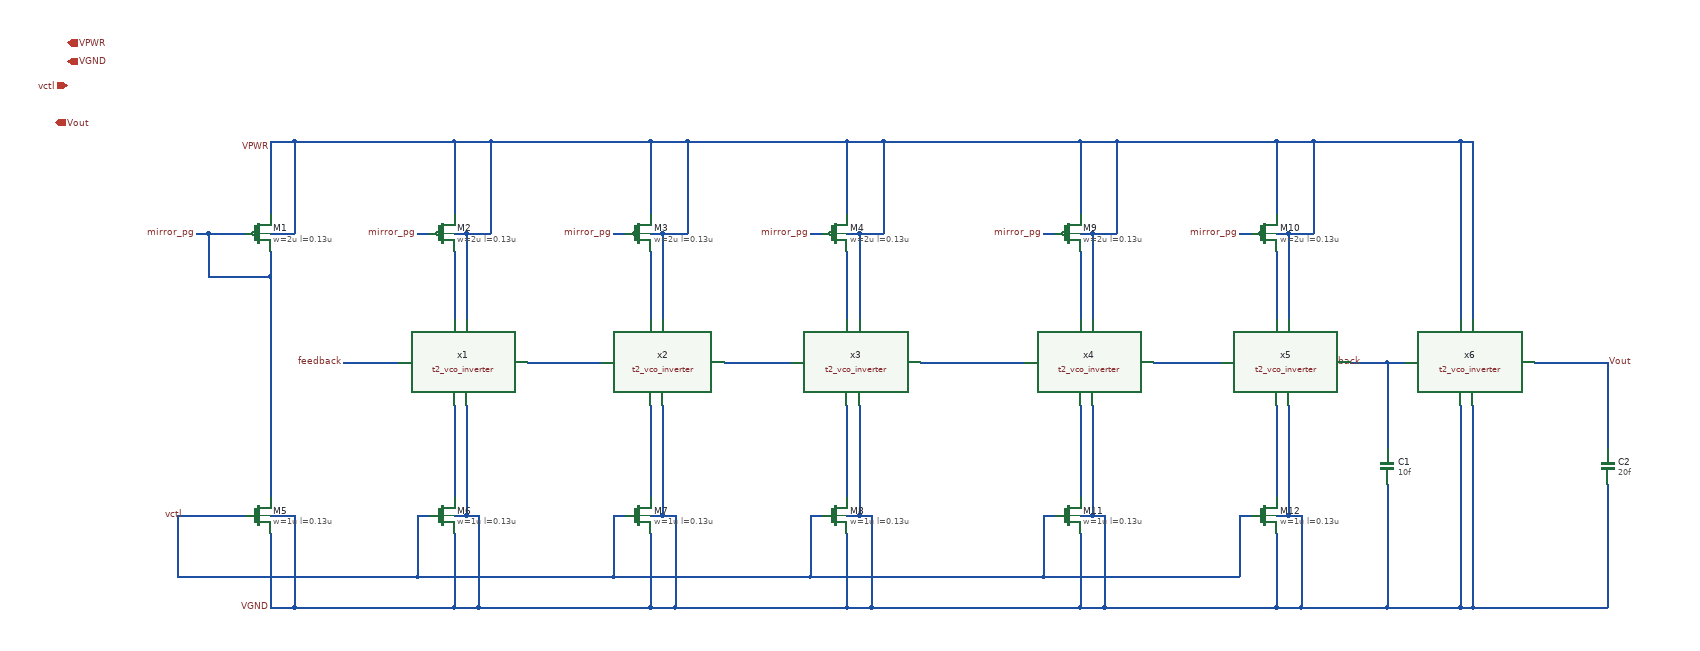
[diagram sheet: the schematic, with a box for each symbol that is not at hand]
v {xschem version=3.4.7 file_version=1.2}
G {}
K {}
V {}
S {}
E {}
N 290 720 550 720 {lab=VGND}
N 100 570 210 570 {lab=vctl}
N 250 570 290 570 {lab=VGND}
N 290 570 290 720 {lab=VGND}
N 250 600 250 720 {lab=VGND}
N 570 570 590 570 {lab=VGND}
N 590 570 590 720 {lab=VGND}
N 550 600 550 720 {lab=VGND}
N 890 570 910 570 {lab=VGND}
N 910 570 910 720 {lab=VGND}
N 870 600 870 720 {lab=VGND}
N 1210 570 1230 570 {lab=VGND}
N 1230 570 1230 720 {lab=VGND}
N 1190 600 1190 720 {lab=VGND}
N 290 -40 550 -40 {lab=VPWR}
N 610 -40 870 -40 {lab=VPWR}
N 930 -40 1190 -40 {lab=VPWR}
N 250 180 250 540 {lab=mirror_pg}
N 150 110 210 110 {lab=mirror_pg}
N 150 110 150 180 {lab=mirror_pg}
N 150 180 250 180 {lab=mirror_pg}
N 250 140 250 180 {lab=mirror_pg}
N 250 110 290 110 {lab=VPWR}
N 250 -40 250 80 {lab=VPWR}
N 570 110 610 110 {lab=VPWR}
N 550 -40 550 80 {lab=VPWR}
N 890 110 930 110 {lab=VPWR}
N 870 -40 870 80 {lab=VPWR}
N 1210 110 1250 110 {lab=VPWR}
N 1190 -40 1190 80 {lab=VPWR}
N 590 720 870 720 {lab=VGND}
N 910 720 1190 720 {lab=VGND}
N 1950 -40 2190 -40 {lab=VPWR}
N 2070 520 2070 720 {lab=VGND}
N 1230 720 1570 720 {lab=VGND}
N 2430 520 2430 720 {lab=VGND}
N 2210 720 2430 720 {lab=VGND}
N 1590 570 1610 570 {lab=VGND}
N 1610 570 1610 720 {lab=VGND}
N 1570 600 1570 720 {lab=VGND}
N 1910 570 1930 570 {lab=VGND}
N 1890 600 1890 720 {lab=VGND}
N 1590 110 1630 110 {lab=VPWR}
N 1570 -40 1570 80 {lab=VPWR}
N 1910 110 1950 110 {lab=VPWR}
N 1890 -40 1890 80 {lab=VPWR}
N 1610 720 1890 720 {lab=VGND}
N 2190 720 2210 720 {lab=VGND}
N 1630 -40 1890 -40 {lab=VPWR}
N 1250 -40 1570 -40 {lab=VPWR}
N 2430 320 2430 460 {lab=Vout}
N 130 110 150 110 {lab=mirror_pg}
N 490 110 510 110 {lab=mirror_pg}
N 810 110 830 110 {lab=mirror_pg}
N 1130 110 1150 110 {lab=mirror_pg}
N 1510 110 1530 110 {lab=mirror_pg}
N 290 -40 290 110 {lab=VPWR}
N 250 -40 290 -40 {lab=VPWR}
N 610 -40 610 110 {lab=VPWR}
N 550 -40 610 -40 {lab=VPWR}
N 1950 -40 1950 110 {lab=VPWR}
N 1890 -40 1950 -40 {lab=VPWR}
N 1630 -40 1630 110 {lab=VPWR}
N 1570 -40 1630 -40 {lab=VPWR}
N 1250 -40 1250 110 {lab=VPWR}
N 1190 -40 1250 -40 {lab=VPWR}
N 930 -40 930 110 {lab=VPWR}
N 870 -40 930 -40 {lab=VPWR}
N 1830 110 1850 110 {lab=mirror_pg}
N 490 570 510 570 {lab=vctl}
N 810 570 830 570 {lab=vctl}
N 1130 570 1150 570 {lab=vctl}
N 1510 570 1530 570 {lab=vctl}
N 1830 570 1850 570 {lab=vctl}
N 250 720 290 720 {lab=VGND}
N 550 720 590 720 {lab=VGND}
N 870 720 910 720 {lab=VGND}
N 1190 720 1230 720 {lab=VGND}
N 1570 720 1610 720 {lab=VGND}
N 1930 570 1930 720 {lab=VGND}
N 1890 720 1930 720 {lab=VGND}
N 100 570 100 670 {lab=vctl}
N 1510 670 1830 670 {lab=vctl}
N 1830 570 1830 670 {lab=vctl}
N 1510 570 1510 670 {lab=vctl}
N 1130 570 1130 670 {lab=vctl}
N 1130 670 1510 670 {lab=vctl}
N 810 670 1130 670 {lab=vctl}
N 810 570 810 670 {lab=vctl}
N 490 670 810 670 {lab=vctl}
N 490 570 490 670 {lab=vctl}
N 100 670 490 670 {lab=vctl}
N 550 140 550 250 {lab=#net1}
N 870 140 870 250 {lab=#net2}
N 890 110 890 250 {lab=VPWR}
N 870 110 890 110 {lab=VPWR}
N 570 110 570 250 {lab=VPWR}
N 550 110 570 110 {lab=VPWR}
N 1930 720 2070 720 {lab=VGND}
N 2070 320 2100 320 {lab=feedback}
N 1910 110 1910 250 {lab=VPWR}
N 1890 110 1910 110 {lab=VPWR}
N 1190 140 1190 250 {lab=#net3}
N 1210 110 1210 250 {lab=VPWR}
N 1190 110 1210 110 {lab=VPWR}
N 370 320 460 320 {lab=feedback}
N 670 320 790 320 {lab=#net4}
N 990 320 1100 320 {lab=#net5}
N 1310 320 1480 320 {lab=#net6}
N 1190 390 1190 540 {lab=#net7}
N 1210 390 1210 570 {lab=VGND}
N 1190 570 1210 570 {lab=VGND}
N 870 390 870 540 {lab=#net8}
N 890 390 890 570 {lab=VGND}
N 870 570 890 570 {lab=VGND}
N 550 390 550 540 {lab=#net9}
N 570 390 570 570 {lab=VGND}
N 550 570 570 570 {lab=VGND}
N 1570 390 1570 540 {lab=#net10}
N 1590 390 1590 570 {lab=VGND}
N 1570 570 1590 570 {lab=VGND}
N 1890 390 1890 540 {lab=#net11}
N 1910 390 1910 570 {lab=VGND}
N 1890 570 1910 570 {lab=VGND}
N 2210 390 2210 720 {lab=VGND}
N 2190 390 2190 720 {lab=VGND}
N 2070 720 2190 720 {lab=VGND}
N 2190 -40 2190 250 {lab=VPWR}
N 2210 -40 2210 250 {lab=VPWR}
N 2190 -40 2210 -40 {lab=VPWR}
N 1890 140 1890 250 {lab=#net12}
N 1590 110 1590 250 {lab=VPWR}
N 1570 110 1590 110 {lab=VPWR}
N 1570 140 1570 250 {lab=#net13}
N 1690 320 1800 320 {lab=#net14}
N 2310 320 2430 320 {lab=Vout}
N 2070 320 2070 460 {lab=feedback}
N 2010 320 2070 320 {lab=feedback}
C {sg13g2_pr/sg13_lv_pmos.sym} 230 110 0 0 {name=M1
l=0.13u
w=2u
ng=1
m=1
model=sg13_lv_pmos
spiceprefix=X
}
C {sg13g2_pr/sg13_lv_pmos.sym} 530 110 0 0 {name=M2
l=0.13u
w=2u
ng=1
m=1
model=sg13_lv_pmos
spiceprefix=X
}
C {sg13g2_pr/sg13_lv_pmos.sym} 850 110 0 0 {name=M3
l=0.13u
w=2u
ng=1
m=1
model=sg13_lv_pmos
spiceprefix=X
}
C {sg13g2_pr/sg13_lv_pmos.sym} 1170 110 0 0 {name=M4
l=0.13u
w=2u
ng=1
m=1
model=sg13_lv_pmos
spiceprefix=X
}
C {sg13g2_pr/sg13_lv_nmos.sym} 230 570 0 0 {name=M5
l=0.13u
w=1u
ng=1
m=1
model=sg13_lv_nmos
spiceprefix=X
}
C {sg13g2_pr/sg13_lv_nmos.sym} 530 570 0 0 {name=M6
l=0.13u
w=1u
ng=1
m=1
model=sg13_lv_nmos
spiceprefix=X
}
C {sg13g2_pr/sg13_lv_nmos.sym} 850 570 0 0 {name=M7
l=0.13u
w=1u
ng=1
m=1
model=sg13_lv_nmos
spiceprefix=X
}
C {sg13g2_pr/sg13_lv_nmos.sym} 1170 570 0 0 {name=M8
l=0.13u
w=1u
ng=1
m=1
model=sg13_lv_nmos
spiceprefix=X
}
C {capa.sym} 2070 490 0 0 {name=C1
m=1
value=10f
footprint=1206
device="ceramic capacitor"}
C {capa.sym} 2430 490 0 0 {name=C2
m=1
value=20f
footprint=1206
device="ceramic capacitor"}
C {sg13g2_pr/sg13_lv_pmos.sym} 1550 110 0 0 {name=M9
l=0.13u
w=2u
ng=1
m=1
model=sg13_lv_pmos
spiceprefix=X
}
C {sg13g2_pr/sg13_lv_pmos.sym} 1870 110 0 0 {name=M10
l=0.13u
w=2u
ng=1
m=1
model=sg13_lv_pmos
spiceprefix=X
}
C {sg13g2_pr/sg13_lv_nmos.sym} 1550 570 0 0 {name=M11
l=0.13u
w=1u
ng=1
m=1
model=sg13_lv_nmos
spiceprefix=X
}
C {sg13g2_pr/sg13_lv_nmos.sym} 1870 570 0 0 {name=M12
l=0.13u
w=1u
ng=1
m=1
model=sg13_lv_nmos
spiceprefix=X
}
C {lab_pin.sym} 370 320 2 1 {name=p15 sig_type=std_logic lab=feedback
}
C {lab_pin.sym} 2030 320 3 1 {name=p6 sig_type=std_logic lab=feedback
}
C {lab_pin.sym} 130 110 2 1 {name=p7 sig_type=std_logic lab=mirror_pg
}
C {lab_pin.sym} 490 110 2 1 {name=p8 sig_type=std_logic lab=mirror_pg
}
C {lab_pin.sym} 810 110 2 1 {name=p9 sig_type=std_logic lab=mirror_pg
}
C {lab_pin.sym} 1130 110 2 1 {name=p10 sig_type=std_logic lab=mirror_pg
}
C {lab_pin.sym} 1510 110 2 1 {name=p11 sig_type=std_logic lab=mirror_pg
}
C {lab_pin.sym} 1830 110 2 1 {name=p12 sig_type=std_logic lab=mirror_pg
}
C {iopin.sym} -80 -200 0 1 {name=p1 lab=VPWR}
C {iopin.sym} -80 -170 0 1 {name=p4 lab=VGND}
C {ipin.sym} -80 -130 0 0 {name=p13 lab=vctl}
C {opin.sym} -100 -70 0 0 {name=p17 lab=Vout}
C {lab_pin.sym} 110 570 2 1 {name=p14 sig_type=std_logic lab=vctl
}
C {lab_pin.sym} 250 720 2 1 {name=p16 sig_type=std_logic lab=VGND
}
C {lab_pin.sym} 250 -30 2 1 {name=p18 sig_type=std_logic lab=VPWR
}
C {lab_pin.sym} 2430 320 2 0 {name=p2 sig_type=std_logic lab=Vout
}
C {/foss/designs/cmos-pll-ihp-sg13g2/Team 2 Design/design_data/xschem/t2_vco_inverter.sym} 560 320 0 0 {name=x1}
C {/foss/designs/cmos-pll-ihp-sg13g2/Team 2 Design/design_data/xschem/t2_vco_inverter.sym} 880 320 0 0 {name=x2}
C {/foss/designs/cmos-pll-ihp-sg13g2/Team 2 Design/design_data/xschem/t2_vco_inverter.sym} 1200 320 0 0 {name=x3}
C {/foss/designs/cmos-pll-ihp-sg13g2/Team 2 Design/design_data/xschem/t2_vco_inverter.sym} 1580 320 0 0 {name=x4}
C {/foss/designs/cmos-pll-ihp-sg13g2/Team 2 Design/design_data/xschem/t2_vco_inverter.sym} 1900 320 0 0 {name=x5}
C {/foss/designs/cmos-pll-ihp-sg13g2/Team 2 Design/design_data/xschem/t2_vco_inverter.sym} 2200 320 0 0 {name=x6}
